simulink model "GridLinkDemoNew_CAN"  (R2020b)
settings: Solver=FixedStepDiscrete  StartTime=0.0  StopTime=inf  RelTol=1e-3  EnableMultiTasking=on
InitFcn:
  | INNER_PWM=1000
  | OUTER_PWM=50000
undefined symbols (not defined in the file): A, ADCIN0, ADCIN1, ADCINA0, ADCINB0, bit, Compare, conversion, CounterCut_Outer, DCAEVT1, DCAEVT1FILT, Digital, Down, ended, Event, Filtered, GPTRIP1SEL, GPTRIP2SEL, hex2dec, identifier, input, Module, Newinv, of, Single, SPS_EMT_TAPAS_2018b, Standard, start, Tmod1, Trip, TZ1, TZ2, U_dc, Up, version, Zone
libraries: tiiqmathlib x63, c2802xlib x31, c2837xDlib x5, c280xlib x5, c28xdmclib x2, simulink x2, svdutilitieslib x1, c2000lib x1, canmsglib x1
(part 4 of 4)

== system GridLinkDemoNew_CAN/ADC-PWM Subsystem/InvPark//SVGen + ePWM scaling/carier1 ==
  Constant : Constant  Value=Tmod1
  Data Store Read : DataStoreRead  DataStoreName=Counter_Outer
  Data Store Read1 : DataStoreRead  DataStoreName=CounterCut_Outer
  Divide : Product  Inputs=*/  RndMeth=Zero  SaturateOnIntegerOverflow=on
  Gain : Gain  Gain=1/2
  Product : Product
  Repeating Sequence : simulink/Sources/Repeating Sequence  Commented=on  rep_seq_t=[0 Tmod1/2 Tmod1]  rep_seq_y=[0 Tmod1 0]
  Subtract : Sum  Inputs=-+
  Switch : Switch  Criteria=u2 > Threshold  Threshold=CounterCut_Outer/2
  tr1 : Outport  VectorParamsAs1DForOutWhenUnconnected=off
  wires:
  Data Store Read/1 -> Subtract/1, Switch/3, Switch/2
  Subtract/1 -> Switch/1
  Switch/1 -> Product/1
  Product/1 -> tr1/1
  Data Store Read1/1 -> Subtract/2, Gain/1
  Divide/1 -> Product/2
  Constant/1 -> Divide/1
  Gain/1 -> Divide/2

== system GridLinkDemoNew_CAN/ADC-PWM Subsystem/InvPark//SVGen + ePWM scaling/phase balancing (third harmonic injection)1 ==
  Tabc : Inport
  Gain1 : Gain  Gain=1/2  SaturateOnIntegerOverflow=on
  Teff : Sum  InputSameDT=on
  Teff1 : Sum  Inputs=-+  InputSameDT=on
  Tmax : MinMax  Function=max  InputSameDT=on  SaturateOnIntegerOverflow=on
  Tmin : MinMax  InputSameDT=on  SaturateOnIntegerOverflow=on
  Tabc_cross : Outport  VectorParamsAs1DForOutWhenUnconnected=off
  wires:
  Gain1/1 -> Teff1/1
  Teff1/1 -> Tabc_cross/1
  Teff/1 -> Gain1/1
  Tmin/1 -> Teff/2
  Tmax/1 -> Teff/1
  Tabc/1 -> Tmax/1, Teff1/2, Tmin/1

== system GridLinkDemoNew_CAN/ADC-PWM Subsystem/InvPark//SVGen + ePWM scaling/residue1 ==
  Tabc : Inport
  Switch : Switch
  Ts : Constant  Value=Tmod1  OutDataTypeStr=single
  V_BR : Sum  InputSameDT=on  SaturateOnIntegerOverflow=on
  Tabc_modified : Outport  VectorParamsAs1DForOutWhenUnconnected=off
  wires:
  Switch/1 -> Tabc_modified/1
  Tabc/1 -> Switch/1, Switch/2, V_BR/1
  V_BR/1 -> Switch/3
  Ts/1 -> V_BR/2

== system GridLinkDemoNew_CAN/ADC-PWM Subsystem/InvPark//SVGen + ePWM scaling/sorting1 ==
  note: T0
  note: T_third_cross
  note: T_first_cross
  note: T_middle
  note: T_offset2
  Tabc_cross : Inport
  Ts : Inport  Port=2
  Add : Sum  Inputs=+-
  Add1 : Sum  Inputs=+-
  Add2 : Sum  Inputs=+-
  Add3 : Sum
  Gain : Gain  Gain=1/2
  MinMax : MinMax  Function=max
  MinMax1 : MinMax
  Tgabc : Outport  VectorParamsAs1DForOutWhenUnconnected=off
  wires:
  Add3/1 -> Tgabc/1
  Add2/1 -> Add3/2
  Gain/1 -> Add2/1
  Add1/1 -> Gain/1
  Add/1 -> Add1/2
  MinMax1/1 -> Add/2, Add2/2
  MinMax/1 -> Add/1
  Ts/1 -> Add1/1
  Tabc_cross/1 -> Add3/1, MinMax/1, MinMax1/1

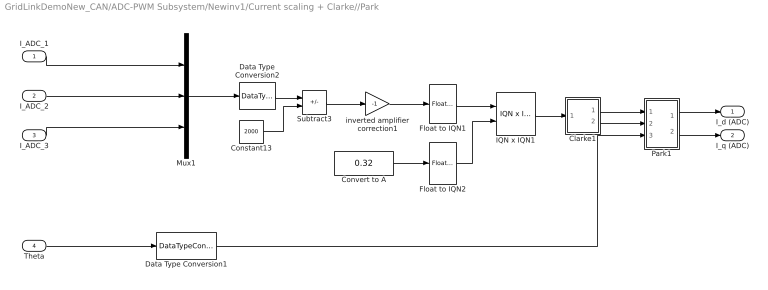
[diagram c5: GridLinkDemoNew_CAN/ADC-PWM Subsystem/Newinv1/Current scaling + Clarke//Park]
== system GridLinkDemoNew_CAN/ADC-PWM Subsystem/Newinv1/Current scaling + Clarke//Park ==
  I_ADC_1 : Inport
  I_ADC_2 : Inport  Port=2
  I_ADC_3 : Inport  Port=3
  Theta : Inport  Port=4
  Clarke1 : Subsystem
  Constant13 : Constant  Value=2000  OutDataTypeStr=single
  Convert to A : Constant  Value=0.32  OutDataTypeStr=single
  Data Type Conversion1 : DataTypeConversion
  Data Type Conversion2 : DataTypeConversion  OutDataTypeStr=single
  Float to IQN1 : tiiqmathlib/Float to IQN  Q_value=16
  Float to IQN2 : tiiqmathlib/Float to IQN  Q_value=16
  IQN x IQN1 : tiiqmathlib/IQN x IQN  multiplyOption=Multiply
  Mux1 : Mux  Inputs=3
  Park1 : Subsystem
  Subtract3 : Sum  Inputs=+-
  inverted amplifier correction1 : Gain  Gain=-1  ParamDataTypeStr=Inherit: Inherit from 'Gain'
  I_d (ADC) : Outport  VectorParamsAs1DForOutWhenUnconnected=off
  I_q (ADC) : Outport  Port=2  VectorParamsAs1DForOutWhenUnconnected=off
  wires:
  Convert to A/1 -> Float to IQN2/1
  Theta/1 -> Data Type Conversion1/1
  Park1/2(q) -> I_q (ADC)/1
  I_ADC_3/1 -> Mux1/3
  I_ADC_2/1 -> Mux1/2
  Clarke1/1(Alpha) -> Park1/1(Alpha)
  I_ADC_1/1 -> Mux1/1
  Mux1/1 -> Data Type Conversion2/1
  inverted amplifier correction1/1 -> Float to IQN1/1
  Data Type Conversion2/1 -> Subtract3/1
  Constant13/1 -> Subtract3/2
  Subtract3/1 -> inverted amplifier correction1/1
  IQN x IQN1/1 -> Clarke1/1(ABC)
  Float to IQN1/1 -> IQN x IQN1/1
  Park1/1(d) -> I_d (ADC)/1
  Float to IQN2/1 -> IQN x IQN1/2
  Data Type Conversion1/1 -> Park1/3(theta)
  Clarke1/2(Beta) -> Park1/2(Beta)

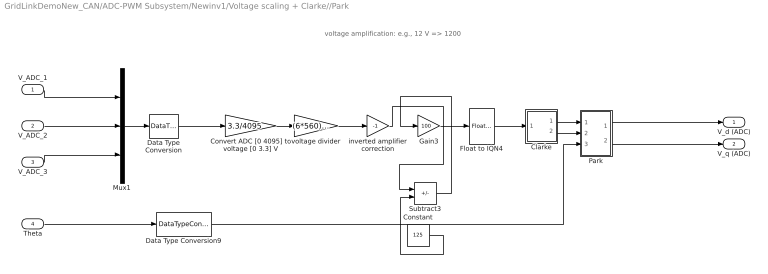
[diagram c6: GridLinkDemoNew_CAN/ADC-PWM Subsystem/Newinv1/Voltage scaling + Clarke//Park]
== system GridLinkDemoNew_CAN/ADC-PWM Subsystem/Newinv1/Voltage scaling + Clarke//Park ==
  note: voltage amplification: e.g., 12 V => 1200
  V_ADC_1 : Inport
  V_ADC_2 : Inport  Port=2
  V_ADC_3 : Inport  Port=3
  Theta : Inport  Port=4
  Clarke : Subsystem
  Constant : Constant  Value=125  OutDataTypeStr=single  SampleTime=-1
  Convert ADC [0 4095] to voltage [0 3.3] V : Gain  Gain=3.3/4095  ParamDataTypeStr=Inherit: Inherit from 'Gain'  OutDataTypeStr=single
  Data Type Conversion : DataTypeConversion  OutDataTypeStr=single
  Data Type Conversion9 : DataTypeConversion
  Float to IQN4 : tiiqmathlib/Float to IQN  Q_value=16
  Gain3 : Gain  Gain=100  ParamDataTypeStr=Inherit: Inherit from 'Gain'
  Mux1 : Mux  Inputs=3
  Park : Subsystem
  Subtract3 : Sum  Inputs=+-
  inverted amplifier correction : Gain  Gain=-1  ParamDataTypeStr=Inherit: Inherit from 'Gain'
  voltage divider : Gain  Gain=(6*560)/(4.7+5.6)  ParamDataTypeStr=Inherit: Inherit from 'Gain'  OutDataTypeStr=single
  V_d (ADC) : Outport  VectorParamsAs1DForOutWhenUnconnected=off
  V_q (ADC) : Outport  Port=2  VectorParamsAs1DForOutWhenUnconnected=off
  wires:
  Data Type Conversion9/1 -> Park/3(theta)
  Gain3/1 -> Float to IQN4/1
  Clarke/1(Alpha) -> Park/1(Alpha)
  Mux1/1 -> Data Type Conversion/1
  Convert ADC [0 4095] to voltage [0 3.3] V/1 -> voltage divider/1
  V_ADC_2/1 -> Mux1/2
  Float to IQN4/1 -> Clarke/1(ABC)
  V_ADC_1/1 -> Mux1/1
  Clarke/2(Beta) -> Park/2(Beta)
  voltage divider/1 -> inverted amplifier correction/1
  Park/1(d) -> V_d (ADC)/1
  Park/2(q) -> V_q (ADC)/1
  V_ADC_3/1 -> Mux1/3
  Theta/1 -> Data Type Conversion9/1
  Data Type Conversion/1 -> Convert ADC [0 4095] to voltage [0 3.3] V/1
  Constant/1 -> Subtract3/2
  inverted amplifier correction/1 -> Subtract3/1
  Subtract3/1 -> Gain3/1

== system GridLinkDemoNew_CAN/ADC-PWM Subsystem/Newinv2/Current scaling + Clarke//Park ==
  I_ADC_1 : Inport
  I_ADC_2 : Inport  Port=2
  I_ADC_3 : Inport  Port=3
  Theta : Inport  Port=4
  Clarke1 : Subsystem
  Constant13 : Constant  Value=2000  OutDataTypeStr=single
  Convert to A : Constant  Value=0.32  OutDataTypeStr=single
  Data Type Conversion1 : DataTypeConversion
  Data Type Conversion2 : DataTypeConversion  OutDataTypeStr=single
  Float to IQN1 : tiiqmathlib/Float to IQN  Q_value=16
  Float to IQN2 : tiiqmathlib/Float to IQN  Q_value=16
  IQN x IQN1 : tiiqmathlib/IQN x IQN  multiplyOption=Multiply
  Mux1 : Mux  Inputs=3
  Park1 : Subsystem
  Subtract3 : Sum  Inputs=+-
  inverted amplifier correction1 : Gain  Gain=-1  ParamDataTypeStr=Inherit: Inherit from 'Gain'
  I_d (ADC) : Outport  VectorParamsAs1DForOutWhenUnconnected=off
  I_q (ADC) : Outport  Port=2  VectorParamsAs1DForOutWhenUnconnected=off
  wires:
  Convert to A/1 -> Float to IQN2/1
  Theta/1 -> Data Type Conversion1/1
  Park1/2(q) -> I_q (ADC)/1
  I_ADC_3/1 -> Mux1/3
  I_ADC_2/1 -> Mux1/2
  Clarke1/1(Alpha) -> Park1/1(Alpha)
  I_ADC_1/1 -> Mux1/1
  Mux1/1 -> Data Type Conversion2/1
  inverted amplifier correction1/1 -> Float to IQN1/1
  Data Type Conversion2/1 -> Subtract3/1
  Constant13/1 -> Subtract3/2
  Subtract3/1 -> inverted amplifier correction1/1
  IQN x IQN1/1 -> Clarke1/1(ABC)
  Float to IQN1/1 -> IQN x IQN1/1
  Park1/1(d) -> I_d (ADC)/1
  Float to IQN2/1 -> IQN x IQN1/2
  Data Type Conversion1/1 -> Park1/3(theta)
  Clarke1/2(Beta) -> Park1/2(Beta)

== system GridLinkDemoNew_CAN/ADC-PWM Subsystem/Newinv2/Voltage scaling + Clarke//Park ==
  V_ADC_1 : Inport
  V_ADC_2 : Inport  Port=2
  V_ADC_3 : Inport  Port=3
  Theta : Inport  Port=4
  Clarke : Subsystem
  Constant : Constant  Value=125  OutDataTypeStr=single  SampleTime=-1
  Convert ADC [0 4095] to voltage [0 3.3] V : Gain  Gain=3.3/4095  ParamDataTypeStr=Inherit: Inherit from 'Gain'  OutDataTypeStr=single
  Data Type Conversion : DataTypeConversion  OutDataTypeStr=single
  Data Type Conversion9 : DataTypeConversion
  Float to IQN4 : tiiqmathlib/Float to IQN  Q_value=16
  Gain3 : Gain  Gain=100  ParamDataTypeStr=Inherit: Inherit from 'Gain'
  Mux1 : Mux  Inputs=3
  Park : Subsystem
  Subtract3 : Sum  Inputs=+-
  inverted amplifier correction : Gain  Gain=-1  ParamDataTypeStr=Inherit: Inherit from 'Gain'
  voltage divider : Gain  Gain=(6*560)/(4.7+5.6)  ParamDataTypeStr=Inherit: Inherit from 'Gain'  OutDataTypeStr=single
  V_d (ADC) : Outport  VectorParamsAs1DForOutWhenUnconnected=off
  V_q (ADC) : Outport  Port=2  VectorParamsAs1DForOutWhenUnconnected=off
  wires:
  Data Type Conversion9/1 -> Park/3(theta)
  Clarke/1(Alpha) -> Park/1(Alpha)
  Mux1/1 -> Data Type Conversion/1
  Convert ADC [0 4095] to voltage [0 3.3] V/1 -> voltage divider/1
  V_ADC_2/1 -> Mux1/2
  Float to IQN4/1 -> Clarke/1(ABC)
  V_ADC_1/1 -> Mux1/1
  Clarke/2(Beta) -> Park/2(Beta)
  Park/1(d) -> V_d (ADC)/1
  Park/2(q) -> V_q (ADC)/1
  V_ADC_3/1 -> Mux1/3
  Theta/1 -> Data Type Conversion9/1
  Gain3/1 -> Float to IQN4/1
  Constant/1 -> Subtract3/2
  Data Type Conversion/1 -> Convert ADC [0 4095] to voltage [0 3.3] V/1
  voltage divider/1 -> inverted amplifier correction/1
  inverted amplifier correction/1 -> Subtract3/1
  Subtract3/1 -> Gain3/1

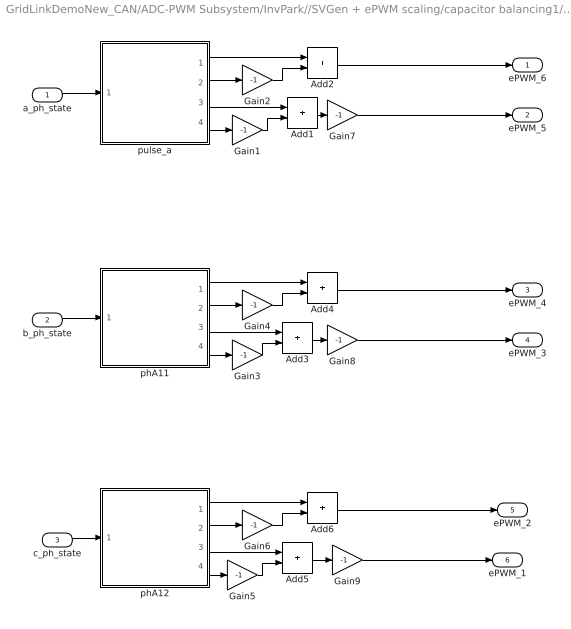
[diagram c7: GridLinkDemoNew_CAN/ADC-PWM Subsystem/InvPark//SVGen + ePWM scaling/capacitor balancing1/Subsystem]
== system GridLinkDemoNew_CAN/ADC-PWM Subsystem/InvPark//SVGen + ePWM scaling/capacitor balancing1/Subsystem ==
  a_ph_state : Inport
  b_ph_state : Inport  Port=2
  c_ph_state : Inport  Port=3
  Add{1..6} (6 alike) : Sum
  Gain{1..9} (9 alike) : Gain  Gain=-1
  phA11 : MATLAB Function  TreatAsAtomicUnit=on
  phA12 : MATLAB Function  TreatAsAtomicUnit=on
  pulse_a : MATLAB Function  TreatAsAtomicUnit=on
  ePWM_6 : Outport  VectorParamsAs1DForOutWhenUnconnected=off
  ePWM_5 : Outport  Port=2  VectorParamsAs1DForOutWhenUnconnected=off
  ePWM_4 : Outport  Port=3  VectorParamsAs1DForOutWhenUnconnected=off
  ePWM_3 : Outport  Port=4  VectorParamsAs1DForOutWhenUnconnected=off
  ePWM_2 : Outport  Port=5  VectorParamsAs1DForOutWhenUnconnected=off
  ePWM_1 : Outport  Port=6  VectorParamsAs1DForOutWhenUnconnected=off
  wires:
  b_ph_state/1 -> phA11/1(state_ph)
  a_ph_state/1 -> pulse_a/1(state_ph)
  c_ph_state/1 -> phA12/1(state_ph)
  Gain2/1 -> Add2/2
  pulse_a/1(s1a) -> Add2/1
  pulse_a/2(s1na) -> Gain2/1
  Gain1/1 -> Add1/2
  pulse_a/3(s2a) -> Add1/1
  pulse_a/4(s2na) -> Gain1/1
  Gain4/1 -> Add4/2
  phA11/3(s2a) -> Add3/1
  phA11/4(s2na) -> Gain3/1
  Gain3/1 -> Add3/2
  phA11/2(s1na) -> Gain4/1
  phA11/1(s1a) -> Add4/1
  Gain6/1 -> Add6/2
  phA12/3(s2a) -> Add5/1
  phA12/4(s2na) -> Gain5/1
  Gain5/1 -> Add5/2
  phA12/2(s1na) -> Gain6/1
  phA12/1(s1a) -> Add6/1
  Add1/1 -> Gain7/1
  Add3/1 -> Gain8/1
  Add5/1 -> Gain9/1
  Add2/1 -> ePWM_6/1
  Gain7/1 -> ePWM_5/1
  Add4/1 -> ePWM_4/1
  Gain8/1 -> ePWM_3/1
  Add6/1 -> ePWM_2/1
  Gain9/1 -> ePWM_1/1

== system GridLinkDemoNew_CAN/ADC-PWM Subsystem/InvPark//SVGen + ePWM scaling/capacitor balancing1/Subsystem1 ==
  note: %--------------------------------------- % this code is identifying the output reference. 1 -> Vdc/2 % 2 -> 0Vdc, 3 -> -Vdc/2 % A is the level signal, determining the reference in which carrier region %---------------------------------------
  level_A : Inport
  level_B : Inport  Port=2
  level_C : Inport  Port=3
  PWM_a : Inport  Port=4
  PWM_b : Inport  Port=5
  PWM_c : Inport  Port=6
  Mux2 : Mux  Inputs=3
  Scope : Scope
  phA2 : MATLAB Function  TreatAsAtomicUnit=on
  phA5 : MATLAB Function  TreatAsAtomicUnit=on
  phA6 : MATLAB Function  TreatAsAtomicUnit=on
  Ph_abc : Outport  VectorParamsAs1DForOutWhenUnconnected=off
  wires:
  PWM_a/1 -> phA2/2(PWM)
  PWM_c/1 -> phA6/2(PWM)
  level_B/1 -> phA5/1(A)
  level_C/1 -> phA6/1(A)
  level_A/1 -> phA2/1(A)
  Mux2/1 -> Ph_abc/1
  phA6/1(PhC) -> Mux2/3
  phA5/1(PhB) -> Mux2/2
  phA2/1(PhA) -> Scope/1, Mux2/1
  PWM_b/1 -> phA5/2(PWM)

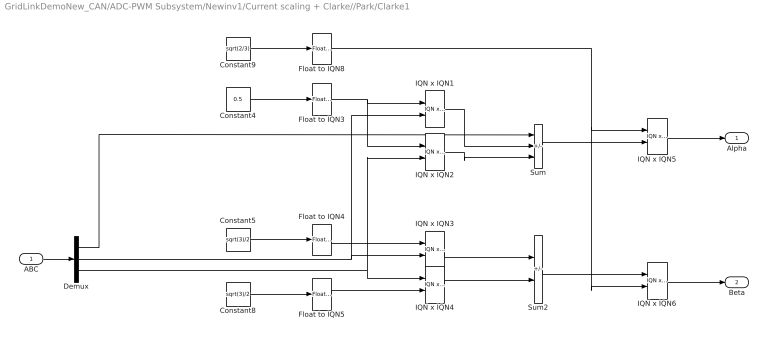
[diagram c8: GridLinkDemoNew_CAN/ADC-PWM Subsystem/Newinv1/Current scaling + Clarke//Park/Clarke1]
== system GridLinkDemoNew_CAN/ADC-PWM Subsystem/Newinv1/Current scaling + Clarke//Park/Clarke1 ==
  ABC : Inport
  Constant4 : Constant  Value=0.5  OutDataTypeStr=single
  Constant5 : Constant  Value=sqrt(3)/2  OutDataTypeStr=single
  Constant8 : Constant  Value=sqrt(3)/2  OutDataTypeStr=single
  Constant9 : Constant  Value=sqrt(2/3)  OutDataTypeStr=single
  Demux : Demux  Outputs=3
  Float to IQN{3..5,8} (4 alike) : tiiqmathlib/Float to IQN  Q_value=16
  IQN x IQN{1..6} (6 alike) : tiiqmathlib/IQN x IQN  multiplyOption=Multiply
  Sum : Sum  Inputs=+--
  Sum2 : Sum  Inputs=+-
  Alpha : Outport  VectorParamsAs1DForOutWhenUnconnected=off
  Beta : Outport  Port=2  VectorParamsAs1DForOutWhenUnconnected=off
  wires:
  Constant5/1 -> Float to IQN4/1
  Float to IQN3/1 -> IQN x IQN2/1, IQN x IQN1/1
  IQN x IQN3/1 -> Sum2/1
  Sum/1 -> IQN x IQN5/2
  IQN x IQN5/1 -> Alpha/1
  IQN x IQN1/1 -> Sum/2
  Constant8/1 -> Float to IQN5/1
  Constant9/1 -> Float to IQN8/1
  Float to IQN5/1 -> IQN x IQN4/2
  IQN x IQN4/1 -> Sum2/2
  Float to IQN8/1 -> IQN x IQN6/2, IQN x IQN5/1
  IQN x IQN2/1 -> Sum/3
  Float to IQN4/1 -> IQN x IQN3/1
  Constant4/1 -> Float to IQN3/1
  ABC/1 -> Demux/1
  Demux/2 -> IQN x IQN1/2, IQN x IQN3/2
  Demux/3 -> IQN x IQN2/2, IQN x IQN4/1
  Demux/1 -> Sum/1
  Sum2/1 -> IQN x IQN6/1
  IQN x IQN6/1 -> Beta/1

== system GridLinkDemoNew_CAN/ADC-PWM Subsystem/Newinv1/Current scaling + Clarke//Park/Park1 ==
  Alpha : Inport
  Beta : Inport  Port=2
  theta : Inport  Port=3
  Product{,1..3} (4 alike) : Product
  Sum2 : Sum  Inputs=|++
  Sum3 : Sum  Inputs=|+-
  cos IQN1 : tiiqmathlib/Trig Fcn IQN  functionOption=_IQcosPU
  sin IQN1 : tiiqmathlib/Trig Fcn IQN  functionOption=_IQsinPU
  d : Outport  VectorParamsAs1DForOutWhenUnconnected=off
  q : Outport  Port=2  VectorParamsAs1DForOutWhenUnconnected=off
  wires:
  Product3/1 -> Sum3/2
  sin IQN1/1 -> Product3/2, Product1/2
  Product2/1 -> Sum3/1
  cos IQN1/1 -> Product2/2, Product/2
  theta/1 -> sin IQN1/1, cos IQN1/1
  Sum2/1 -> d/1
  Product/1 -> Sum2/1
  Alpha/1 -> Product3/1, Product/1
  Product1/1 -> Sum2/2
  Beta/1 -> Product2/1, Product1/1
  Sum3/1 -> q/1

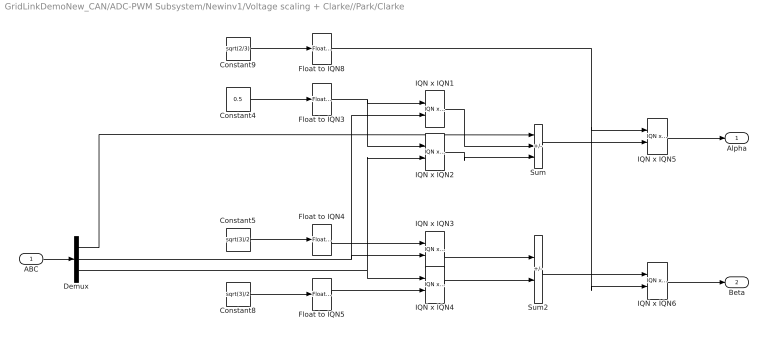
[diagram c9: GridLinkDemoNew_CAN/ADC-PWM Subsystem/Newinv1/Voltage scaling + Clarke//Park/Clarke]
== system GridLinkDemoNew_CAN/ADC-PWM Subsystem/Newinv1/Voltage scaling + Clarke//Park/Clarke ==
  ABC : Inport
  Constant4 : Constant  Value=0.5  OutDataTypeStr=single
  Constant5 : Constant  Value=sqrt(3)/2  OutDataTypeStr=single
  Constant8 : Constant  Value=sqrt(3)/2  OutDataTypeStr=single
  Constant9 : Constant  Value=sqrt(2/3)  OutDataTypeStr=single
  Demux : Demux  Outputs=3
  Float to IQN{3..5,8} (4 alike) : tiiqmathlib/Float to IQN  Q_value=16
  IQN x IQN{1..6} (6 alike) : tiiqmathlib/IQN x IQN  multiplyOption=Multiply
  Sum : Sum  Inputs=+--
  Sum2 : Sum  Inputs=+-
  Alpha : Outport  VectorParamsAs1DForOutWhenUnconnected=off
  Beta : Outport  Port=2  VectorParamsAs1DForOutWhenUnconnected=off
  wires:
  Constant5/1 -> Float to IQN4/1
  Float to IQN3/1 -> IQN x IQN2/1, IQN x IQN1/1
  IQN x IQN3/1 -> Sum2/1
  Sum/1 -> IQN x IQN5/2
  IQN x IQN5/1 -> Alpha/1
  IQN x IQN1/1 -> Sum/2
  Constant8/1 -> Float to IQN5/1
  Constant9/1 -> Float to IQN8/1
  Float to IQN5/1 -> IQN x IQN4/2
  IQN x IQN4/1 -> Sum2/2
  Float to IQN8/1 -> IQN x IQN6/2, IQN x IQN5/1
  IQN x IQN2/1 -> Sum/3
  Float to IQN4/1 -> IQN x IQN3/1
  Constant4/1 -> Float to IQN3/1
  ABC/1 -> Demux/1
  Demux/2 -> IQN x IQN1/2, IQN x IQN3/2
  Demux/3 -> IQN x IQN2/2, IQN x IQN4/1
  Demux/1 -> Sum/1
  Sum2/1 -> IQN x IQN6/1
  IQN x IQN6/1 -> Beta/1

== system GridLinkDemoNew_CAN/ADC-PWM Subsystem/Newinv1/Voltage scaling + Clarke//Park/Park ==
  Alpha : Inport
  Beta : Inport  Port=2
  theta : Inport  Port=3
  Product{,1..3} (4 alike) : Product
  Sum2 : Sum  Inputs=|++
  Sum3 : Sum  Inputs=|+-
  cos IQN1 : tiiqmathlib/Trig Fcn IQN  functionOption=_IQcosPU
  sin IQN1 : tiiqmathlib/Trig Fcn IQN  functionOption=_IQsinPU
  d : Outport  VectorParamsAs1DForOutWhenUnconnected=off
  q : Outport  Port=2  VectorParamsAs1DForOutWhenUnconnected=off
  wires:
  Product3/1 -> Sum3/2
  sin IQN1/1 -> Product3/2, Product1/2
  Product2/1 -> Sum3/1
  cos IQN1/1 -> Product2/2, Product/2
  theta/1 -> sin IQN1/1, cos IQN1/1
  Sum2/1 -> d/1
  Product/1 -> Sum2/1
  Alpha/1 -> Product3/1, Product/1
  Product1/1 -> Sum2/2
  Beta/1 -> Product2/1, Product1/1
  Sum3/1 -> q/1

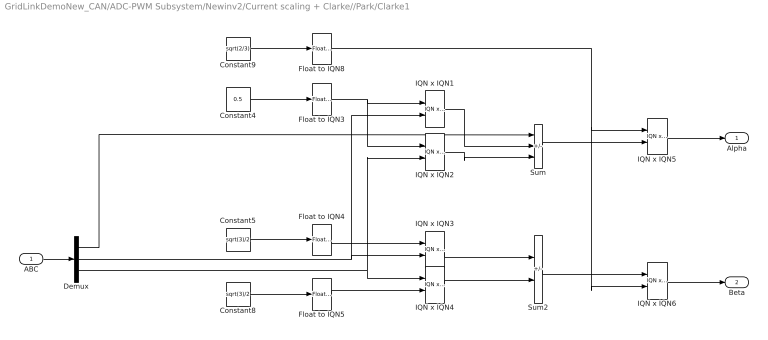
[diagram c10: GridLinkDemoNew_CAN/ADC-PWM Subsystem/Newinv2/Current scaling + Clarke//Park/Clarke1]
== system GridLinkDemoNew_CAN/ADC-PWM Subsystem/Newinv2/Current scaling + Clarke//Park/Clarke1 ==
  ABC : Inport
  Constant4 : Constant  Value=0.5  OutDataTypeStr=single
  Constant5 : Constant  Value=sqrt(3)/2  OutDataTypeStr=single
  Constant8 : Constant  Value=sqrt(3)/2  OutDataTypeStr=single
  Constant9 : Constant  Value=sqrt(2/3)  OutDataTypeStr=single
  Demux : Demux  Outputs=3
  Float to IQN{3..5,8} (4 alike) : tiiqmathlib/Float to IQN  Q_value=16
  IQN x IQN{1..6} (6 alike) : tiiqmathlib/IQN x IQN  multiplyOption=Multiply
  Sum : Sum  Inputs=+--
  Sum2 : Sum  Inputs=+-
  Alpha : Outport  VectorParamsAs1DForOutWhenUnconnected=off
  Beta : Outport  Port=2  VectorParamsAs1DForOutWhenUnconnected=off
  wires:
  Constant5/1 -> Float to IQN4/1
  Float to IQN3/1 -> IQN x IQN2/1, IQN x IQN1/1
  IQN x IQN3/1 -> Sum2/1
  Sum/1 -> IQN x IQN5/2
  IQN x IQN5/1 -> Alpha/1
  IQN x IQN1/1 -> Sum/2
  Constant8/1 -> Float to IQN5/1
  Constant9/1 -> Float to IQN8/1
  Float to IQN5/1 -> IQN x IQN4/2
  IQN x IQN4/1 -> Sum2/2
  Float to IQN8/1 -> IQN x IQN6/2, IQN x IQN5/1
  IQN x IQN2/1 -> Sum/3
  Float to IQN4/1 -> IQN x IQN3/1
  Constant4/1 -> Float to IQN3/1
  ABC/1 -> Demux/1
  Demux/2 -> IQN x IQN1/2, IQN x IQN3/2
  Demux/3 -> IQN x IQN2/2, IQN x IQN4/1
  Demux/1 -> Sum/1
  Sum2/1 -> IQN x IQN6/1
  IQN x IQN6/1 -> Beta/1

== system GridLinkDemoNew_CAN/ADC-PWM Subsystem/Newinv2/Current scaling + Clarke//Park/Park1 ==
  Alpha : Inport
  Beta : Inport  Port=2
  theta : Inport  Port=3
  Product{,1..3} (4 alike) : Product
  Sum2 : Sum  Inputs=|++
  Sum3 : Sum  Inputs=|+-
  cos IQN1 : tiiqmathlib/Trig Fcn IQN  functionOption=_IQcosPU
  sin IQN1 : tiiqmathlib/Trig Fcn IQN  functionOption=_IQsinPU
  d : Outport  VectorParamsAs1DForOutWhenUnconnected=off
  q : Outport  Port=2  VectorParamsAs1DForOutWhenUnconnected=off
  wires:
  Product3/1 -> Sum3/2
  sin IQN1/1 -> Product3/2, Product1/2
  Product2/1 -> Sum3/1
  cos IQN1/1 -> Product2/2, Product/2
  theta/1 -> sin IQN1/1, cos IQN1/1
  Sum2/1 -> d/1
  Product/1 -> Sum2/1
  Alpha/1 -> Product3/1, Product/1
  Product1/1 -> Sum2/2
  Beta/1 -> Product2/1, Product1/1
  Sum3/1 -> q/1

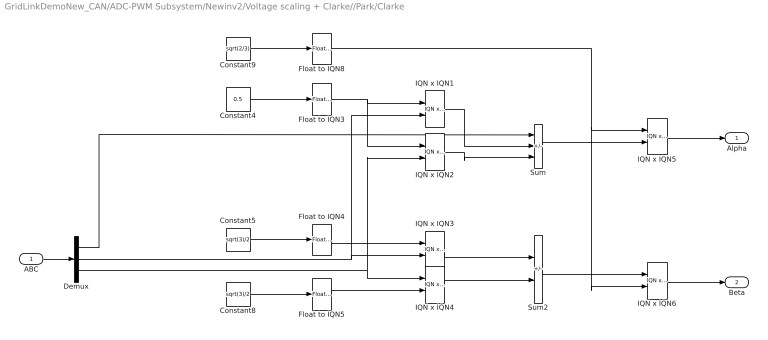
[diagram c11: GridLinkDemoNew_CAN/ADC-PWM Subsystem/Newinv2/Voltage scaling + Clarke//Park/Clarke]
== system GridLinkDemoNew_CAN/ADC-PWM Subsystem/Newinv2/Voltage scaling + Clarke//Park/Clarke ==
  ABC : Inport
  Constant4 : Constant  Value=0.5  OutDataTypeStr=single
  Constant5 : Constant  Value=sqrt(3)/2  OutDataTypeStr=single
  Constant8 : Constant  Value=sqrt(3)/2  OutDataTypeStr=single
  Constant9 : Constant  Value=sqrt(2/3)  OutDataTypeStr=single
  Demux : Demux  Outputs=3
  Float to IQN{3..5,8} (4 alike) : tiiqmathlib/Float to IQN  Q_value=16
  IQN x IQN{1..6} (6 alike) : tiiqmathlib/IQN x IQN  multiplyOption=Multiply
  Sum : Sum  Inputs=+--
  Sum2 : Sum  Inputs=+-
  Alpha : Outport  VectorParamsAs1DForOutWhenUnconnected=off
  Beta : Outport  Port=2  VectorParamsAs1DForOutWhenUnconnected=off
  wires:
  Constant5/1 -> Float to IQN4/1
  Float to IQN3/1 -> IQN x IQN2/1, IQN x IQN1/1
  IQN x IQN3/1 -> Sum2/1
  Sum/1 -> IQN x IQN5/2
  IQN x IQN5/1 -> Alpha/1
  IQN x IQN1/1 -> Sum/2
  Constant8/1 -> Float to IQN5/1
  Constant9/1 -> Float to IQN8/1
  Float to IQN5/1 -> IQN x IQN4/2
  IQN x IQN4/1 -> Sum2/2
  Float to IQN8/1 -> IQN x IQN6/2, IQN x IQN5/1
  IQN x IQN2/1 -> Sum/3
  Float to IQN4/1 -> IQN x IQN3/1
  Constant4/1 -> Float to IQN3/1
  ABC/1 -> Demux/1
  Demux/2 -> IQN x IQN1/2, IQN x IQN3/2
  Demux/3 -> IQN x IQN2/2, IQN x IQN4/1
  Demux/1 -> Sum/1
  Sum2/1 -> IQN x IQN6/1
  IQN x IQN6/1 -> Beta/1

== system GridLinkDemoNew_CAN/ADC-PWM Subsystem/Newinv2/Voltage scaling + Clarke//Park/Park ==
  Alpha : Inport
  Beta : Inport  Port=2
  theta : Inport  Port=3
  Product{,1..3} (4 alike) : Product
  Sum2 : Sum  Inputs=|++
  Sum3 : Sum  Inputs=|+-
  cos IQN1 : tiiqmathlib/Trig Fcn IQN  functionOption=_IQcosPU
  sin IQN1 : tiiqmathlib/Trig Fcn IQN  functionOption=_IQsinPU
  d : Outport  VectorParamsAs1DForOutWhenUnconnected=off
  q : Outport  Port=2  VectorParamsAs1DForOutWhenUnconnected=off
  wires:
  Product3/1 -> Sum3/2
  sin IQN1/1 -> Product3/2, Product1/2
  Product2/1 -> Sum3/1
  cos IQN1/1 -> Product2/2, Product/2
  theta/1 -> sin IQN1/1, cos IQN1/1
  Sum2/1 -> d/1
  Product/1 -> Sum2/1
  Alpha/1 -> Product3/1, Product/1
  Product1/1 -> Sum2/2
  Beta/1 -> Product2/1, Product1/1
  Sum3/1 -> q/1

== matlab function GridLinkDemoNew_CAN/ADC-PWM
Subsystem/InvPark//SVGen + ePWM scaling/capacitor balancing1/Subsystem/phA11 ==
function [s1a,s1na,s2a,s2na] = fcn(state_ph)
%#codegen

%----------phA---------
if state_ph == 1 
    s1a = 1;
    s1na = 0;
    s2a = 0;
    s2na = 1;
elseif state_ph == 3 
    s1a = 0;
    s1na = 1;
    s2a = 1;
    s2na = 0;
else 
    s1a = 0;
    s1na = 1;
    s2a = 0;
    s2na = 1;
end
%-------------------------------

== matlab function GridLinkDemoNew_CAN/ADC-PWM
Subsystem/InvPark//SVGen + ePWM scaling/capacitor balancing1/Subsystem/phA12 ==
function [s1a,s1na,s2a,s2na] = fcn(state_ph)
%#codegen

%----------phA---------
if state_ph == 1 
    s1a = 1;
    s1na = 0;
    s2a = 0;
    s2na = 1;
elseif state_ph == 3 
    s1a = 0;
    s1na = 1;
    s2a = 1;
    s2na = 0;
else 
    s1a = 0;
    s1na = 1;
    s2a = 0;
    s2na = 1;
end
%-------------------------------

== matlab function GridLinkDemoNew_CAN/ADC-PWM
Subsystem/InvPark//SVGen + ePWM scaling/capacitor balancing1/Subsystem/pulse_a ==
function [s1a,s1na,s2a,s2na] = fcn(state_ph)
%#codegen
%----------phA---------
if state_ph == 1 
    s1a = 1;
    s1na = 0;
    s2a = 0;
    s2na = 1;
elseif state_ph == 3 
    s1a = 0;
    s1na = 1;
    s2a = 1;
    s2na = 0;
else 
    s1a = 0;
    s1na = 1;
    s2a = 0;
    s2na = 1;
end
%-------------------------------

== matlab function GridLinkDemoNew_CAN/ADC-PWM
Subsystem/InvPark//SVGen + ePWM scaling/capacitor balancing1/Subsystem1/phA2 ==
function PhA = fcn(A,PWM)
%#codegen
%---------------------------------------
% this code is identifying the output reference. 1 -> Vdc/2
% 2 -> 0Vdc, 3 -> -Vdc/2
% A is the level signal, determining the reference in which carrier region
%---------------------------------------
PhA = 2;
if (A == 1) && (PWM == 1) 
    PhA = 1; 
end
if (A == 1) && (PWM == 0)
    PhA = 2; 
end
if (A == 0) && (PWM == 1)
    PhA = 2; 
end
if (A == 0) && (PWM == 0)
    PhA = 3; 
end
%-------------------------------

== matlab function GridLinkDemoNew_CAN/ADC-PWM
Subsystem/InvPark//SVGen + ePWM scaling/capacitor balancing1/Subsystem1/phA5 ==
function PhB = fcn(A,PWM)
%#codegen
PhB = 2;
if (A == 1) && (PWM == 1) 
    PhB = 1; 
end
if (A == 1) && (PWM == 0)
    PhB = 2; 
end
if (A == 0) && (PWM == 1)
    PhB = 2; 
end
if (A == 0) && (PWM == 0)
    PhB = 3; 
end
%-------------------------------

== matlab function GridLinkDemoNew_CAN/ADC-PWM
Subsystem/InvPark//SVGen + ePWM scaling/capacitor balancing1/Subsystem1/phA6 ==
function PhC = fcn(A,PWM)
%#codegen
PhC = 2;
if (A == 1) && (PWM == 1) 
    PhC = 1; 
end
if (A == 1) && (PWM == 0)
    PhC = 2; 
end
if (A == 0) && (PWM == 1)
    PhC = 2; 
end
if (A == 0) && (PWM == 0)
    PhC = 3; 
end
%-------------------------------

== matlab function GridLinkDemoNew_CAN/ADC-PWM
Subsystem/InvPark//SVGen + ePWM scaling/capacitor balancing1/state to vec ==
function Vector = fcn(state)
%#codegen
%---------------------------------------------------------
% this code is identifying the 19 space vector points for three level
% inverter
%---------------------------------------------------------
Vector = 1;
if (state == 111) || (state == 222) || (state == 333)
    Vector = 1; 
end
if (state == 122) || (state == 233)
    Vector = 2; 
end
if (state == 112) || (state == 223)
    Vector = 3; 
end
if (state == 212) || (state == 323)
    Vector = 4; 
end
if (state == 211) || (state == 322)
    Vector = 5; 
end
if (state == 221) || (state == 332)
    Vector = 6; 
end
if (state == 121) || (state == 232)
    Vector = 7; 
end
if (state == 133)
    Vector = 8; 
end
if (state == 123)
    Vector = 9; 
end
if (state == 113)
    Vector = 10; 
end
if (state == 213)
    Vector = 11; 
end
if (state == 313)
    Vector = 12; 
end
if (state == 312)
    Vector = 13; 
end
if (state == 311)
    Vector = 14; 
end
if (state == 321)
    Vector = 15; 
end
if (state == 331)
    Vector = 16; 
end
if (state == 231)
    Vector = 17; 
end
if (state == 131)
    Vector = 18; 
end
if (state == 132)
    Vector = 19; 
end
%-------------------------------

== matlab function GridLinkDemoNew_CAN/ADC-PWM
Subsystem/InvPark//SVGen + ePWM scaling/capacitor balancing1/state to vector ==
function [a,b,c] = fcn(state)
%#codegen
% this code is separating the three phase states example 123 into 1, 2 and
% 3 for the reference to each phase
%---------------------------------------
a = floor(state/100);
b = floor(10*((state/100)-floor(state/100)));
c = ((state)-10*floor(state/10));
%-------------------------------

== matlab function GridLinkDemoNew_CAN/ADC-PWM
Subsystem/InvPark//SVGen + ePWM scaling/capacitor balancing1/vector to state ==
function state = fcn(Vc1,Vc2,Vector,state1,diff_V)

% state = state1;
%#codegen
% state = 333;
if Vector == 2
    if Vc1 - Vc2 > diff_V
        state = 233;
    elseif  Vc1 - Vc2 < -diff_V
        state = 122;
    else
        state = state1;
    end
elseif Vector == 3
    if Vc1 - Vc2 > diff_V
        state = 223;
    elseif Vc1 - Vc2 < -diff_V
        state = 112;
    else
        state = state1;
    end
elseif Vector == 4
    if Vc1 - Vc2 > diff_V
        state = 323;
    elseif Vc1 - Vc2 < -diff_V 
        state = 212;
    else
        state = state1;
    end
elseif Vector == 5
    if Vc1 - Vc2 > diff_V
        state = 322;
    elseif Vc1 - Vc2 < -diff_V 
        state = 211;
    else
        state = state1;
    end    
elseif Vector == 6
    if Vc1 - Vc2 > diff_V
        state = 332;
    elseif Vc1 - Vc2 < -diff_V
        state = 221;
    else
        state = state1;
    end
elseif Vector == 7
    if Vc1 - Vc2 > diff_V
        state = 232;
    elseif Vc1 - Vc2 < -diff_V 
        state = 121;
    else
        state = state1;
    end
else
    state = state1;
end
%-------------------------------
